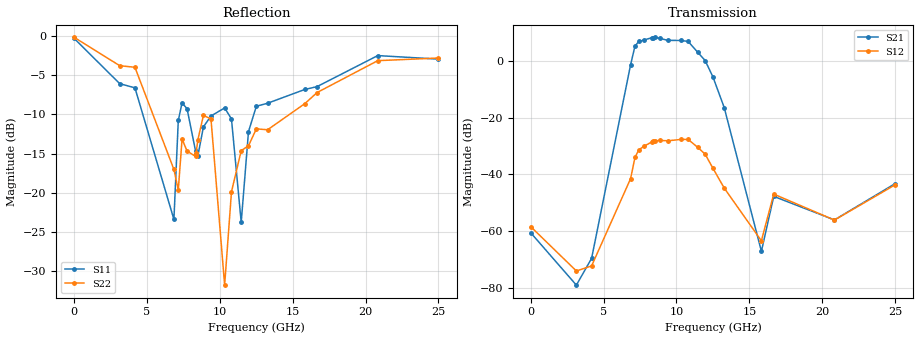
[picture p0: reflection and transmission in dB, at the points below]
!Agilent Technologies,E8364B,MY43040894,A.07.50.67
!Agilent E8364B: A.07.50.67
!Date: Wednesday, July 07, 2021 13:15:15
!Correction: S11(Full 2 Port(1,2))
!S21(Full 2 Port(1,2))
!S12(Full 2 Port(1,2))
!S22(Full 2 Port(1,2))
!S2P File: Measurements: S11, S21, S12, S22:
# Hz S  dB  R 50
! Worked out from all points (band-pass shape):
!   8001 points, 10 MHz to 25 GHz, reference 50 ohm
!   highest |S21| = 8.42 dB at 8.494 GHz (marker M1); lowest = -79.1 dB at 3.131 GHz (marker M2)
!   |S21| within 3 dB of the highest: 7.159 GHz to 11.23 GHz (4.075 GHz wide, 44.3 % of centre)
!   lowest |S11| = -23.8 dB at 11.47 GHz (marker M3), VSWR 1.14, Z = 55.2 - j4.36 ohm
!   |S11| at or under -10 dB: 6.428 GHz to 7.195 GHz (767.4 MHz wide, 11.3 % of centre); 7.898 GHz to 9.516 GHz (1.618 GHz wide, 18.6 % of centre); 10.71 GHz to 12.19 GHz (1.488 GHz wide, 13 % of centre)
!   |S22| runs from -32.6 to -0.1 dB; largest |S21 - S12| = 2.6
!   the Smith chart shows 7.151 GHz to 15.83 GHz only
!   S11 on the Smith chart (normalised r, x): 7.151 GHz: 0.57, -0.17; 8.375 GHz: 1.42, +0.05; 10.33 GHz: 0.56, +0.34; 11.97 GHz: 0.61, -0.01; 13.27 GHz: 2.19, +0.03; 15.83 GHz: 0.41, -0.27
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1e7  -0.27 -3.7  -60.64 -112.1  -58.47 97.6  -0.13 -4.4
3.130626e9  -6.05 134.3  -79.08 22.3  -74.08 -90.7  -3.75 -122.0
4.177082e9  -6.59 21.3  -69.63 68.7  -72.30 -163.4  -3.96 -153.2
6.851012e9  -23.43 -174.5  -1.26 -31.7  -41.48 -147.6  -17.04 65.0
7.150892e9  -10.76 -152.3  5.32 -122.4  -34.00 149.5  -19.68 -157.1
7.410164e9  -8.52 168.6  6.97 165.2  -31.34 85.4  -13.13 162.2
7.750652e9  -9.25 122.9  7.46 92.0  -30.07 17.5  -14.67 140.2
8.341041e9  -14.72 15.4  8.36 -13.1  -28.42 -81.8  -15.37 168.8
8.375402e9  -15.11 5.7  8.38 -19.0  -28.35 -87.3  -14.88 169.3
8.494105e9  -15.31 -30.0  8.42 -38.9  -28.15 -106.3  -13.24 168.0
8.875202e9  -11.58 -107.7  8.08 -99.6  -27.96 -164.2  -10.11 143.3
9.393745e9  -10.19 -159.7  7.36 -172.5  -28.11 124.8  -10.56 97.1
1.033087e10  -9.16 130.4  7.33 59.9  -27.61 -0.3  -31.84 -54.3
1.079943e10  -10.57 79.9  6.97 -11.5  -27.63 -69.1  -19.90 140.8
1.146792e10  -23.81 -37.5  3.12 -122.2  -30.45 -177.0  -14.62 44.7
1.196772e10  -12.19 -177.7  0.23 167.5  -32.84 116.7  -14.01 -41.0
1.2505e10  -8.95 82.9  -5.60 80.3  -37.84 44.4  -11.83 -117.2
1.327344e10  -8.56 1.0  -16.35 -34.2  -44.79 -47.3  -11.96 127.9
1.582555e10  -6.80 -144.3  -67.12 -3.5  -63.43 -29.5  -8.62 107.9
1.667208e10  -6.43 173.8  -47.74 -0.4  -46.94 -1.1  -7.19 66.2
2.083604e10  -2.46 -17.4  -56.05 -90.5  -56.11 -89.9  -3.11 -54.3
2.5e10  -2.91 -103.7  -43.24 -86.5  -43.65 -80.7  -2.77 -119.5
